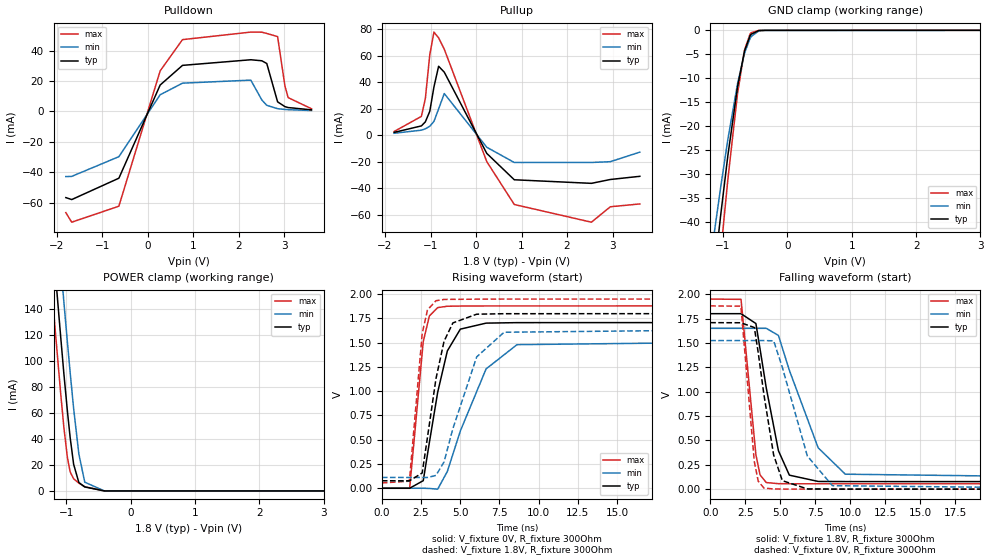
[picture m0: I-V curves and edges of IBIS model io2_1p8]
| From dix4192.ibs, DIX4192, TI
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|   io2_1p8 Model
[Model]   io2_1p8
Model_type   I/O
Polarity   Non-Inverting
Enable   Active-Low
Vinl = 0.54
Vinh = 1.26
Vmeas = 0.9
Vref = 0
Cref = 2pF
Rref = 100000
|   typ   min   max
C_comp   31.1631pF   25.2142pF   36.9521pF
|C_comp_pullup   31.7413pF   25.9187pF   37.6397pF
|C_comp_pulldown   31.5959pF   25.8011pF   37.465pF
[Model spec]
|subparameter
Vinl   0.54   0.495   0.585
Vinh   1.26   1.155   1.365
| Where nom  PVT is Nominal Process, 1.8V, 27C
|   Fast PVT is Strong Process,  1.95V, -40C
|   Slow PVT is Weak Process,   1.65V, 105C
[Voltage Range]   1.8   1.65   1.95
[Temperature Range]   27   105   -40
[Pullup Reference]   1.8   1.65   1.95
[Pulldown Reference]   0   0   0
[Power Clamp Reference]   1.8   1.65   1.95
[GND Clamp Reference]   0   0   0
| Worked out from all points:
|   slope of the pulldown table from 0 to 0.27 V, typ, clamps not added: 15.7 ohm
|   slope of the pullup table from 0 to 0.27 V, typ, clamps not added: 17.7 ohm
|   GND clamp passes 1 mA (typ) near -0.57 V on its own axis
|   POWER clamp passes 1 mA (typ) near -0.56 V on its own axis
|   falling waveform, V_fixture 1.8V, R_fixture 300Ohm: 20-80 % time 1.28ns typ, 2.34ns min, 717ps max; typ from 1.8 V to 0.077 V
|   rising waveform, V_fixture 0V, R_fixture 300Ohm: 20-80 % time 1.18ns typ, 2.17ns min, 638ps max; typ from 0 V to 1.71 V
|   rising waveform, V_fixture 1.8V, R_fixture 300Ohm: 20-80 % time 1.04ns typ, 1.8ns min, 589ps max; typ from 0.077 V to 1.8 V
|   falling waveform, V_fixture 0V, R_fixture 300Ohm: 20-80 % time 1.08ns typ, 1.84ns min, 633ps max; typ from 1.71 V to 0 V
[Pulldown]
|   Voltage   I(typ)   I(min)   I(max)
-1.8V     -56.63mA   -42.81mA   -66.52mA
-1.67V    -57.93mA   -42.68mA   -72.81mA
-633.6mV  -43.88mA   -29.73mA   -62.29mA
273.6mV   17.4mA     10.99mA    26.7mA
765mV     30.33mA    18.63mA    47.27mA
2.266V    34.03mA    20.63mA    52.22mA
2.509V    33.35mA    7.565mA    52.15mA
2.617V    31.56mA    4.064mA    51.33mA
2.855V    6.344mA    1.84mA     49.25mA
3.017V    3.179mA    1.318mA    16.68mA
3.087V    2.59mA     1.171mA    9.115mA
3.6V      1.075mA    640.9uA    1.804mA
[GND Clamp]
|   Voltage   I(typ)   I(min)   I(max)
-1.8V     -142.6mA   -115.6mA   -175.2mA
-1.174V   -55.13mA   -45.96mA   -66.77mA
-1.114V   -47.78mA   -40.09mA   -57.8mA
-1.033V   -38.14mA   -32.37mA   -45.96mA
-925.2mV  -26.13mA   -22.74mA   -31.09mA
-774mV    -11.72mA   -11.06mA   -13.11mA
-666mV    -4.302mA   -4.761mA   -4.076mA
-579.6mV  -1.122mA   -1.655mA   -756.7uA
-563.4mV  -812.6uA   -1.29mA    -503.6uA
-444.6mV  -43.3uA    -131.6uA   -12uA
-342mV    -1.685uA   -11.56uA   -47.19nA
3.6V      0A         0A         0A
[Pullup]
|   Voltage   I(typ)   I(min)   I(max)
-1.8V     2.198mA    1.55mA     2.867mA
-1.201V   7.084mA    3.863mA    14.25mA
-1.114V   10.13mA    4.875mA    27.64mA
-1.017V   18.04mA    6.818mA    60.52mA
-925.2mV  36.38mA    10.47mA    77.67mA
-822.6mV  51.95mA    19.8mA     73.34mA
-698.4mV  47.53mA    31.43mA    64.82mA
235.8mV   -13.6mA    -8.983mA   -19.78mA
840.6mV   -33.45mA   -20.44mA   -52.05mA
2.536V    -36.14mA   -20.43mA   -65.37mA
2.952V    -33.24mA   -19.84mA   -53.76mA
3.6V      -30.85mA   -12.66mA   -51.64mA
[POWER Clamp]
|   Voltage   I(typ)   I(min)   I(max)
-1.8V     564.8mA    620.9mA    520.8mA
-1.233V   204.8mA    261.9mA    159.6mA
-1.168V   165.5mA    222.3mA    120.5mA
-1.087V   117.7mA    173.8mA    74.13mA
-1.039V   90.27mA    145.4mA    48.83mA
-984.6mV  61.6mA     114.7mA    25.82mA
-941.4mV  40.98mA    91.12mA    14.65mA
-887.4mV  20.49mA    63.43mA    9.326mA
-806.4mV  6.463mA    28.45mA    6.043mA
-714.6mV  3.048mA    6.727mA    3.292mA
-412.2mV  29.86uA    75.2uA     8.811uA
3.6V      0A         0A         0A
[Ramp]
R_load = 300
|   typ   min   max
dV/dt_r   1.02457/1.17804e-09   0.914694/2.17755e-09   1.12794/6.37261e-10
dV/dt_f   1.03368/1.28451e-09   0.923169/2.3426e-09   1.13713/7.16673e-10
[Falling Waveform]
V_fixture = 1.8V
V_fixture_min = 1.65V
V_fixture_max = 1.95V
R_fixture = 300Ohm
C_fixture = 0F
|   Time   V(typ)   V(min)   V(max)
0s        1.8V       1.65V      1.95V
2.202ns   1.8V       1.65V      1.947V
3.264ns   1.699V     1.65V      351.8mV
3.562ns   1.436V     1.65V      146.6mV
4.003ns   1.039V     1.65V      68.03mV
4.872ns   394.9mV    1.577V     56.39mV
5.654ns   143.7mV    1.219V     55.32mV
7.71ns    79.23mV    424.3mV    55.28mV
9.649ns   78.01mV    153.6mV    55.24mV
33.34ns   77.2mV     111.4mV    54.79mV
[Rising Waveform]
V_fixture = 0V
V_fixture_min = 0V
V_fixture_max = 0V
R_fixture = 300Ohm
C_fixture = 0F
|   Time   V(typ)   V(min)   V(max)
0s        -191.4nV   -2.372uV   -256.3nV
1.774ns   143.9uV    76.32uV    -288.9uV
2.641ns   78.33mV    114.8uV    1.513V
3.032ns   472.3mV    -2.028mV   1.775V
3.562ns   989.8mV    -9.382mV   1.862V
4.179ns   1.416V     173.6mV    1.876V
5.007ns   1.64V      590.3mV    1.878V
6.65ns    1.702V     1.23V      1.879V
8.621ns   1.707V     1.48V      1.879V
33.34ns   1.708V     1.524V     1.88V
[Rising Waveform]
V_fixture = 1.8V
V_fixture_min = 1.65V
V_fixture_max = 1.95V
R_fixture = 300Ohm
C_fixture = 0F
|   Time   V(typ)   V(min)   V(max)
0s        77.2mV     111.4mV    54.79mV
1.757ns   76.77mV    111.1mV    72.97mV
2.573ns   157.6mV    111mV      1.594V
2.911ns   526.5mV    111mV      1.838V
3.451ns   1.128V     132.1mV    1.933V
3.967ns   1.515V     271mV      1.946V
4.531ns   1.704V     614.2mV    1.947V
6.05ns    1.794V     1.354V     1.949V
7.799ns   1.799V     1.608V     1.95V
33.34ns   1.8V       1.65V      1.95V
[Falling Waveform]
|Gnd
V_fixture = 0V
V_fixture_min = 0V
V_fixture_max = 0V
R_fixture = 300Ohm
C_fixture = 0F
|   Time   V(typ)   V(min)   V(max)
0s        1.708V     1.524V     1.88V
2.191ns   1.707V     1.524V     1.877V
3.153ns   1.658V     1.524V     278.4mV
3.431ns   1.399V     1.524V     81.72mV
3.837ns   969.3mV    1.524V     11.57mV
4.531ns   350.7mV    1.522V     1.89mV
5.151ns   87.35mV    1.25V      949.9uV
6.936ns   2.529mV    340.6mV    491.6uV
8.724ns   743.7uV    35.8mV     458.3uV
33.34ns   -167.7nV   -2.395uV   -247nV
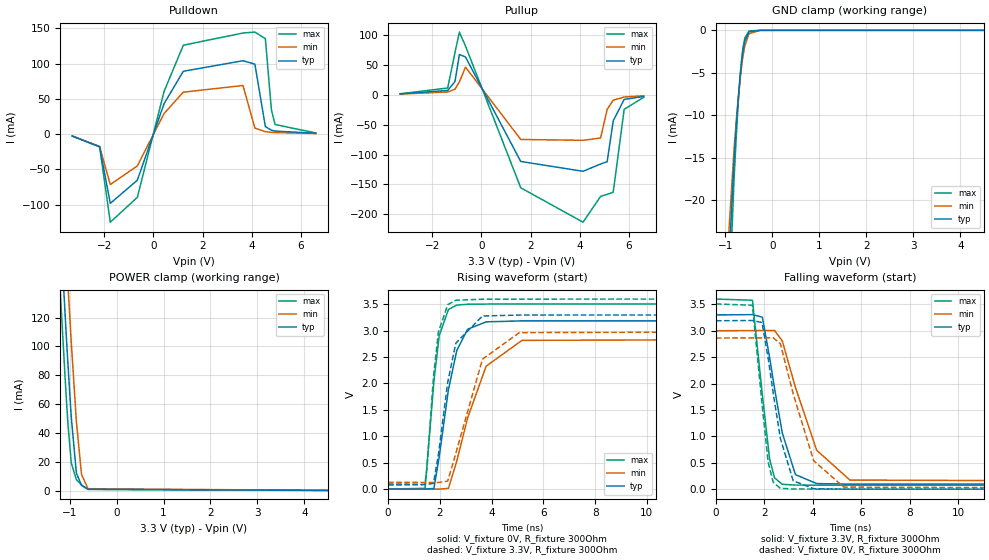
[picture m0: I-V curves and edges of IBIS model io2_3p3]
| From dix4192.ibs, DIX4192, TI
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|   io2_3p3 Model
[Model]   io2_3p3
Model_type   I/O
Polarity   Non-Inverting
Enable   Active-Low
Vinl = 0.99
Vinh = 2.31
Vmeas = 1.65
Vref = 0
Cref = 2pF
Rref = 100000
|   typ   min   max
C_comp   31.0198pF   25.2142pF   36.9519pF
|C_comp_pullup   31.4512pF   25.5641pF   37.4648pF
|C_comp_pulldown   31.7412pF   25.9197pF   37.6393pF
[Model spec]
|subparameter
Vinl   0.99   0.90   1.08
Vinh   2.31   2.10   2.52
| Where nom  PVT is Nominal Process, 3.3V, 27C
|   Fast PVT is Strong Process,  3.6V, -40C
|   Slow PVT is Weak Process,   3.0V, 105C
[Voltage Range]   3.3   3   3.6
[Temperature Range]   27   105   -40
[Pullup Reference]   3.3   3   3.6
[Pulldown Reference]   0   0   -0
[Power Clamp Reference]   3.3   3   3.6
[GND Clamp Reference]   0   0   0
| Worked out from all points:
|   slope of the pulldown table from 0 to 0.495 V, typ, clamps not added: 10.2 ohm
|   slope of the pullup table from 0 to 0.495 V, typ, clamps not added: 11.2 ohm
|   GND clamp passes 1 mA (typ) near -0.57 V on its own axis
|   POWER clamp passes 1 mA (typ) near -0.59 V on its own axis
|   falling waveform, V_fixture 3.3V, R_fixture 300Ohm: 20-80 % time 735ps typ, 1.22ns min, 459ps max; typ from 3.3 V to 0.095 V
|   rising waveform, V_fixture 0V, R_fixture 300Ohm: 20-80 % time 628ps typ, 1.07ns min, 377ps max; typ from 0 V to 3.19 V
|   rising waveform, V_fixture 3.3V, R_fixture 300Ohm: 20-80 % time 594ps typ, 983ps min, 362ps max; typ from 0.095 V to 3.3 V
|   falling waveform, V_fixture 0V, R_fixture 300Ohm: 20-80 % time 666ps typ, 1.07ns min, 423ps max; typ from 3.19 V to 0 V
[Pulldown]
|   Voltage   I(typ)   I(min)   I(max)
-3.3V     -2.852mA   -2.596mA   -2.852mA
-2.191V   -18.08mA   -17.62mA   -17.58mA
-1.756V   -98.1mA    -71.45mA   -124.8mA
-656.7mV  -65.33mA   -45.08mA   -89.62mA
432.3mV   43.23mA    29.27mA    60.55mA
1.214V    89.07mA    59.43mA    126mA
3.64V     104mA      68.94mA    143.3mA
4.125V    99.15mA    8.551mA    144.6mA
4.551V    10.64mA    3.483mA    135.2mA
4.798V    5.618mA    2.568mA    34.1mA
4.947V    4.357mA    2.216mA    13.59mA
6.6V      1.224mA    869.1uA    1.663mA
[GND Clamp]
|   Voltage   I(typ)   I(min)   I(max)
-3.3V     -1.043A    -967.2mA   -1.114A
-1.152V   -52.4mA    -43.78mA   -63.44mA
-815.1mV  -15.27mA   -13.97mA   -17.55mA
-765.6mV  -11.03mA   -10.49mA   -12.26mA
-726mV    -8.025mA   -7.984mA   -8.54mA
-686.4mV  -5.441mA   -5.769mA   -5.411mA
-656.7mV  -3.83mA    -4.334mA   -3.536mA
-627mV    -2.531mA   -3.117mA   -2.114mA
-587.4mV  -1.301mA   -1.855mA   -911.6uA
-498.3mV  -181.2uA   -402.6uA   -76.66uA
-260.7mV  0A         -988.2nA   0A
6.6V      0A         0A         0A
[Pullup]
|   Voltage   I(typ)   I(min)   I(max)
-3.3V     1.193mA    955.2uA    1.362mA
-1.369V   6.903mA    4.325mA    11mA
-1.073V   21.93mA    9.068mA    70.24mA
-894.3mV  66.92mA    21.2mA     104.3mA
-646.8mV  62.78mA    45.89mA    81.1mA
1.601V    -111.6mA   -74.87mA   -155.5mA
4.135V    -128mA     -76.27mA   -212.9mA
4.848V    -115.8mA   -72.43mA   -169.9mA
5.115V    -112mA     -24.74mA   -166.4mA
5.362V    -43.81mA   -9.261mA   -162.9mA
5.808V    -8.053mA   -4.052mA   -24.52mA
6.6V      -3.082mA   -1.984mA   -4.667mA
[POWER Clamp]
|   Voltage   I(typ)   I(min)   I(max)
-3.3V     1.547A     1.6A       1.506A
-1.261V   221.8mA    278.9mA    176.5mA
-1.201V   185.4mA    242.4mA    140.3mA
-1.181V   173.4mA    230.3mA    128.4mA
-1.092V   120.7mA    176.8mA    76.94mA
-1.063V   103.7mA    159.3mA    60.97mA
-1.033V   87.14mA    142.1mA    46.08mA
-963.6mV  51.24mA    103.1mA    19.41mA
-854.7mV  12.41mA    48.08mA    7.805mA
-745.8mV  3.823mA    11.52mA    4.15mA
-607.2mV  1.171mA    1.445mA    1.051mA
6.6V      0A         0A         0A
[Ramp]
R_load = 300
|   typ   min   max
dV/dt_r   1.91352/6.27172e-10   1.71722/1.0692e-09   2.10458/3.75584e-10
dV/dt_f   1.92296/7.33822e-10   1.72387/1.21729e-09   2.11532/4.59333e-10
[Falling Waveform]
V_fixture = 3.3V
V_fixture_min = 3V
V_fixture_max = 3.6V
R_fixture = 300Ohm
C_fixture = 0F
|   Time   V(typ)   V(min)   V(max)
0s        3.3V       3V         3.6V
1.503ns   3.305V     3.003V     3.578V
1.912ns   3.257V     3.004V     1.788V
2.211ns   2.497V     3.005V     572.2mV
2.417ns   1.903V     3.006V     214mV
2.736ns   1.062V     2.805V     91.54mV
3.277ns   275.2mV    1.928V     77.32mV
4.152ns   106.1mV    737.9mV    75.81mV
5.522ns   96.24mV    172.5mV    75.09mV
33.34ns   95.07mV    126.9mV    74.47mV
[Rising Waveform]
V_fixture = 0V
V_fixture_min = 0V
V_fixture_max = 0V
R_fixture = 300Ohm
C_fixture = 0F
|   Time   V(typ)   V(min)   V(max)
0s        -43.37nV   -573nV     -482.9nV
1.43ns    296.6uV    110.2uV    13.26mV
1.771ns   10.78mV    136.6uV    2.042V
1.976ns   608.8mV    -2.323mV   2.907V
2.333ns   1.883V     13.27mV    3.402V
2.655ns   2.625V     527.9mV    3.486V
3.075ns   3.028V     1.348V     3.502V
3.79ns    3.168V     2.329V     3.505V
5.174ns   3.187V     2.817V     3.507V
33.34ns   3.189V     2.862V     3.508V
[Rising Waveform]
V_fixture = 3.3V
V_fixture_min = 3V
V_fixture_max = 3.6V
R_fixture = 300Ohm
C_fixture = 0F
|   Time   V(typ)   V(min)   V(max)
0s        95.07mV    126.9mV    74.47mV
1.421ns   89.31mV    125.4mV    82.85mV
1.503ns   88.97mV    125.4mV    387.7mV
1.755ns   106.8mV    125.1mV    2.128V
1.946ns   658.3mV    124.9mV    2.975V
2.306ns   2.025V     150.2mV    3.494V
2.618ns   2.763V     675.4mV    3.578V
3.648ns   3.279V     2.46V      3.597V
5.072ns   3.297V     2.964V     3.599V
33.34ns   3.3V       3V         3.6V
[Falling Waveform]
|Gnd
V_fixture = 0V
V_fixture_min = 0V
V_fixture_max = 0V
R_fixture = 300Ohm
C_fixture = 0F
|   Time   V(typ)   V(min)   V(max)
0s        3.189V     2.862V     3.508V
1.503ns   3.194V     2.865V     3.483V
1.898ns   3.156V     2.866V     1.616V
2.151ns   2.482V     2.866V     513.1mV
2.359ns   1.823V     2.867V     130.6mV
2.655ns   961.9mV    2.755V     16.47mV
3.184ns   159.5mV    1.806V     2.745mV
4.027ns   8.659mV    539mV      1.341mV
5.273ns   1.101mV    38.63mV    607uV
33.34ns   -68.95nV   -586.3nV   -335.5nV
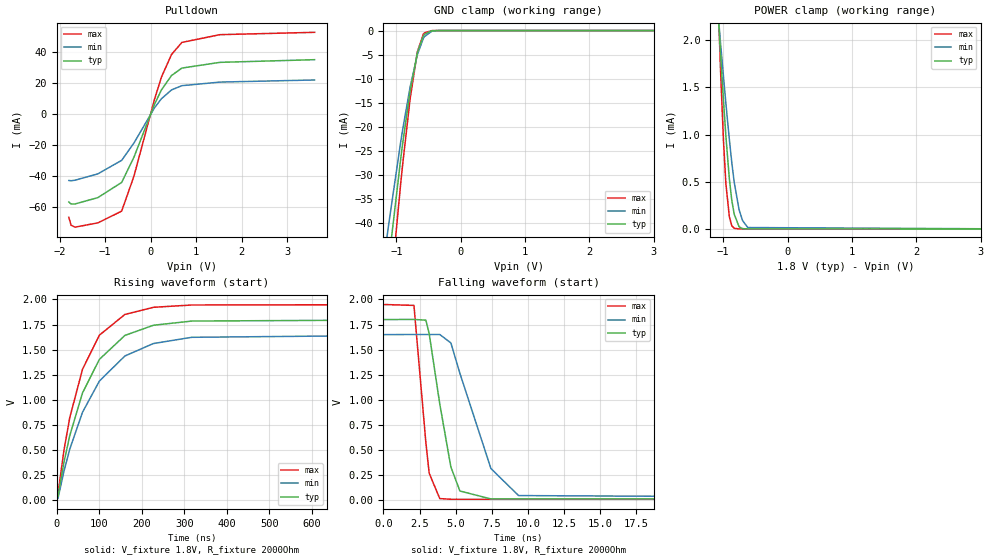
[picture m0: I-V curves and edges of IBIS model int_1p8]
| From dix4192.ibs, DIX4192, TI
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|   int_1p8 Model
[Model]   int_1p8
Model_type   I/O_open_drain
Polarity   Non-Inverting
Enable   Active-Low
Vinl = 0.54
Vinh = 1.26
Vmeas = 0.9
Vref = 1.8
Cref = 2pF
Rref = 2000
|   typ   min   max
C_comp   30.5945pF   24.7576pF   36.4452pF
|C_comp_pulldown   31.0229pF   25.2142pF   36.7811pF
[Model spec]
|subparameter
Vinl   0.54   0.495   0.585
Vinh   1.26   1.155   1.365
| Where nom  PVT is Nominal Process, 1.8V, 27C
|   Fast PVT is Strong Process,  1.95V, -40C
|   Slow PVT is Weak Process,   1.65V, 105C
[Voltage Range]   1.8   1.65   1.95
[Temperature Range]   27   105   -40
[Pullup Reference]   1.8   1.65   1.95
[Pulldown Reference]   0   0   0
[Power Clamp Reference]   1.8   1.65   1.95
[GND Clamp Reference]   0   0   0
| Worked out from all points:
|   slope of the pulldown table from 0 to 0.27 V, typ, clamps not added: 15.7 ohm
|   GND clamp passes 1 mA (typ) near -0.57 V on its own axis
|   POWER clamp passes 1 mA (typ) near -0.96 V on its own axis
|   falling waveform, V_fixture 1.8V, R_fixture 2000Ohm: 20-80 % time 1.21ns typ, 2.17ns min, 678ps max; typ from 1.8 V to 0.011 V
|   rising waveform, V_fixture 1.8V, R_fixture 2000Ohm: 20-80 % time 90.5ns typ, 107ns min, 74.2ns max; typ from 0.011 V to 1.8 V
[Pulldown]
|   Voltage   I(typ)   I(min)   I(max)
-1.8V     -56.63mA   -42.82mA   -66.47mA
-1.751V   -57.93mA   -43mA      -71.57mA
-1.665V   -57.93mA   -42.66mA   -72.84mA
-1.163V   -53.86mA   -38.58mA   -70.1mA
-639mV    -44.08mA   -29.88mA   -62.54mA
-369mV    -27.85mA   -18.73mA   -40.08mA
84.6mV    6.258mA    3.979mA    9.545mA
235.8mV   15.47mA    9.791mA    23.71mA
457.2mV   24.69mA    15.43mA    38.22mA
684mV     29.46mA    18.14mA    45.96mA
1.521V    33.14mA    20.45mA    50.95mA
3.6V      34.86mA    21.81mA    52.45mA
[GND Clamp]
|   Voltage   I(typ)   I(min)   I(max)
-1.8V     -142.4mA   -115.4mA   -175.1mA
-1.174V   -55.01mA   -45.84mA   -66.67mA
-1.114V   -47.68mA   -39.97mA   -57.72mA
-930.6mV  -26.64mA   -23.12mA   -31.76mA
-898.2mV  -23.26mA   -20.41mA   -27.55mA
-784.8mV  -12.59mA   -11.75mA   -14.21mA
-671.4mV  -4.573mA   -4.985mA   -4.394mA
-579.6mV  -1.113mA   -1.637mA   -749.3uA
-563.4mV  -804.9uA   -1.274mA   -497.5uA
-444.6mV  -42.08uA   -128uA     -11.6uA
-347.4mV  -1.972uA   -12.75uA   -92.62nA
3.6V      0A         0A         0A
[POWER Clamp]
|   Voltage   I(typ)   I(min)   I(max)
-1.8V     11.51mA    8.536mA    18.67mA
-1.076V   2.271mA    2.258mA    2.367mA
-1.039V   1.838mA    1.954mA    1.652mA
-995.4mV  1.365mA    1.616mA    939.7uA
-957.6mV  983.6uA    1.33mA     479.5uA
-903.6mV  528.3uA    946.2uA    129.2uA
-865.8mV  303.5uA    703.7uA    34.04uA
-828mV    156.5uA    493.5uA    6.61uA
-752.4mV  22.76uA    203uA      76.37nA
-698.4mV  3.563uA    88.91uA    0A
-617.4mV  42.07nA    14.98uA    0A
3.6V      0A         0A         0A
[Ramp]
R_load = 2000
|   typ   min   max
dV/dt_r   1.07313/9.04998e-08   0.980109/1.06656e-07   1.16511/7.42567e-08
dV/dt_f   1.07313/1.20868e-09   0.980109/2.17304e-09   1.16511/6.77688e-10
[Falling Waveform]
V_fixture = 1.8V
V_fixture_min = 1.65V
V_fixture_max = 1.95V
R_fixture = 2000Ohm
C_fixture = 0F
|   Time   V(typ)   V(min)   V(max)
0s        1.8V       1.65V      1.95V
2.113ns   1.801V     1.651V     1.941V
2.938ns   1.794V     1.651V     573.3mV
3.168ns   1.659V     1.651V     267.9mV
3.9ns     958.2mV    1.651V     15.69mV
4.667ns   330.8mV    1.567V     8.787mV
5.294ns   90.93mV    1.263V     8.786mV
7.437ns   12.07mV    315.4mV    8.785mV
9.351ns   12.07mV    45.55mV    8.784mV
50ns      11.45mV    16.48mV    8.144mV
[Rising Waveform]
V_fixture = 1.8V
V_fixture_min = 1.65V
V_fixture_max = 1.95V
R_fixture = 2000Ohm
C_fixture = 0F
|   Time   V(typ)   V(min)   V(max)
0s        11.45mV    16.48mV    8.144mV
3.344ns   34.82mV    16.53mV    59.49mV
17.44ns   377.4mV    287.8mV    496.6mV
31.11ns   643.4mV    509.4mV    823.3mV
61.02ns   1.069V     876mV      1.305V
100.6ns   1.403V     1.187V     1.644V
160.6ns   1.642V     1.437V     1.851V
227.4ns   1.743V     1.561V     1.922V
317.4ns   1.785V     1.623V     1.945V
1us       1.8V       1.65V      1.95V
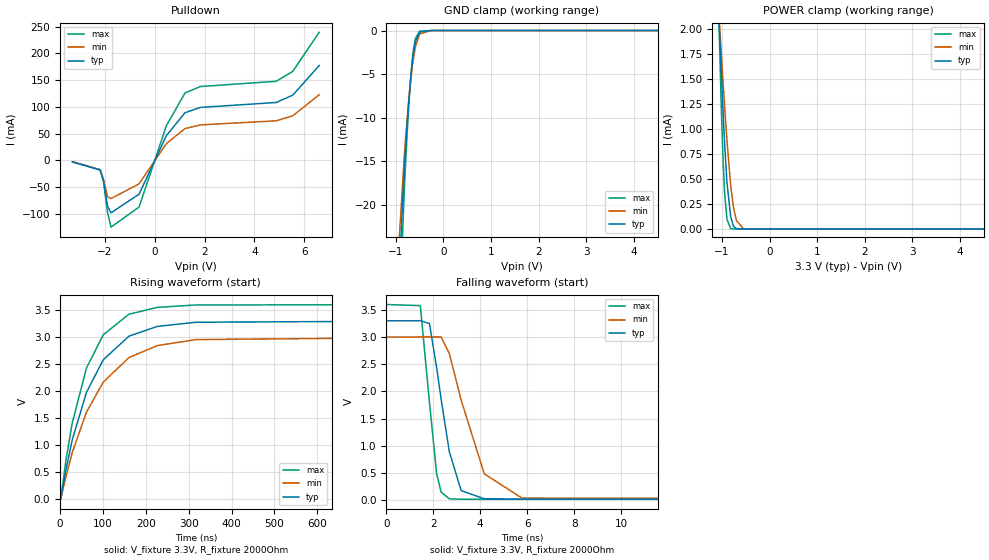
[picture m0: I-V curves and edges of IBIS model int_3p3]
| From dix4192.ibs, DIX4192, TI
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|   int_3p3 Model
[Model]   int_3p3
Model_type   I/O_open_drain
Polarity   Non-Inverting
Enable   Active-Low
Vinl = 0.99
Vinh = 2.31
Vmeas = 1.65
Vref = 3.3
Cref = 2pF
Rref = 2000
|   typ   min   max
C_comp   30.5943pF   24.6405pF   36.4452pF
|C_comp_pulldown   31.3045pF   25.4466pF   37.1164pF
[Model spec]
|subparameter
Vinl   0.99   0.90   1.08
Vinh   2.31   2.10   2.52
| Where nom  PVT is Nominal Process, 3.3V, 27C
|   Fast PVT is Strong Process,  3.6V, -40C
|   Slow PVT is Weak Process,   3.0V, 105C
[Voltage Range]   3.3   3   3.6
[Temperature Range]   27   105   -40
[Pullup Reference]   3.3   3   3.6
[Pulldown Reference]   0   0   0
[Power Clamp Reference]   3.3   3   3.6
[GND Clamp Reference]   0   0   0
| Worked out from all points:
|   slope of the pulldown table from 0 to 0.495 V, typ, clamps not added: 10.2 ohm
|   GND clamp passes 1 mA (typ) near -0.57 V on its own axis
|   POWER clamp passes 1 mA (typ) near -0.96 V on its own axis
|   falling waveform, V_fixture 3.3V, R_fixture 2000Ohm: 20-80 % time 708ps typ, 1.17ns min, 441ps max; typ from 3.3 V to 0.014 V
|   rising waveform, V_fixture 3.3V, R_fixture 2000Ohm: 20-80 % time 90.2ns typ, 106ns min, 74ns max; typ from 0.014 V to 3.3 V
[Pulldown]
|   Voltage   I(typ)   I(min)   I(max)
-3.3V     -2.85mA    -2.595mA   -2.851mA
-2.191V   -18.04mA   -17.58mA   -17.54mA
-2.062V   -36.44mA   -34.55mA   -37.56mA
-1.894V   -85.34mA   -67.98mA   -96.98mA
-1.756V   -98.15mA   -71.47mA   -124.9mA
-627mV    -63.22mA   -43.86mA   -87.29mA
471.9mV   46.52mA    31.49mA    65.2mA
1.214V    89.07mA    59.43mA    126mA
1.828V    99.03mA    66.3mA     138.1mA
4.877V    108.3mA    73.98mA    147.9mA
5.541V    122mA      83.38mA    166.5mA
6.6V      177.4mA    122.7mA    239.5mA
[GND Clamp]
|   Voltage   I(typ)   I(min)   I(max)
-3.3V     -1.043A    -967.2mA   -1.114A
-1.152V   -52.29mA   -43.66mA   -63.35mA
-815.1mV  -15.23mA   -13.91mA   -17.52mA
-765.6mV  -11mA      -10.44mA   -12.23mA
-726mV    -8.002mA   -7.941mA   -8.52mA
-686.4mV  -5.423mA   -5.733mA   -5.395mA
-656.7mV  -3.815mA   -4.304mA   -3.522mA
-627mV    -2.537mA   -3.091mA   -2.102mA
-587.4mV  -1.291mA   -1.835mA   -903.6uA
-498.3mV  -177.8uA   -394.8uA   -74.76uA
-260.7mV  0A         -939.5nA   0A
6.6V      0A         0A         0A
[POWER Clamp]
|   Voltage   I(typ)   I(min)   I(max)
-3.3V     31.5mA     22.11mA    54.06mA
-1.063V   2.111mA    2.146mA    2.099mA
-1.053V   1.997mA    2.066mA    1.911mA
-1.013V   1.555mA    1.753mA    1.213mA
-983.4mV  1.24mA     1.524mA    773.4uA
-943.8mV  854.9uA    1.228mA    359.1uA
-894.3mV  464.9uA    884uA      96.47uA
-815.1mV  120.1uA    431uA      3.52uA
-755.7mV  25.1uA     212uA      71.04nA
-696.3mV  3.16uA     85.5uA     0A
-547.8mV  0A         1.94uA     0A
6.6V      0A         0A         0A
[Ramp]
R_load = 2000
|   typ   min   max
dV/dt_r   1.97146/9.02394e-08   1.78857/1.06414e-07   2.15331/7.39951e-08
dV/dt_f   1.97146/7.06755e-10   1.78857/1.17256e-09   2.15331/4.4149e-10
[Falling Waveform]
V_fixture = 3.3V
V_fixture_min = 3V
V_fixture_max = 3.6V
R_fixture = 2000Ohm
C_fixture = 0F
|   Time   V(typ)   V(min)   V(max)
0s        3.3V       3V         3.6V
1.449ns   3.301V     3.001V     3.579V
1.838ns   3.249V     3.001V     1.799V
2.143ns   2.439V     3.001V     486.4mV
2.335ns   1.858V     3.001V     143.4mV
2.682ns   892.9mV    2.7V       21.05mV
3.188ns   171.8mV    1.839V     12.43mV
4.171ns   20.78mV    481.3mV    12.42mV
5.776ns   15.51mV    34.03mV    12.42mV
50ns      14.24mV    19.04mV    11.14mV
[Rising Waveform]
V_fixture = 3.3V
V_fixture_min = 3V
V_fixture_max = 3.6V
R_fixture = 2000Ohm
C_fixture = 0F
|   Time   V(typ)   V(min)   V(max)
0s        14.24mV    19.04mV    11.14mV
1.503ns   12.35mV    15.54mV    -1.174mV
14.06ns   564mV      432mV      749.5mV
28.17ns   1.097V     863mV      1.408V
61.38ns   1.976V     1.609V     2.425V
100.5ns   2.577V     2.165V     3.039V
160.5ns   3.014V     2.619V     3.42V
226.6ns   3.195V     2.84V      3.547V
316.6ns   3.272V     2.951V     3.591V
1us       3.3V       3V         3.6V
